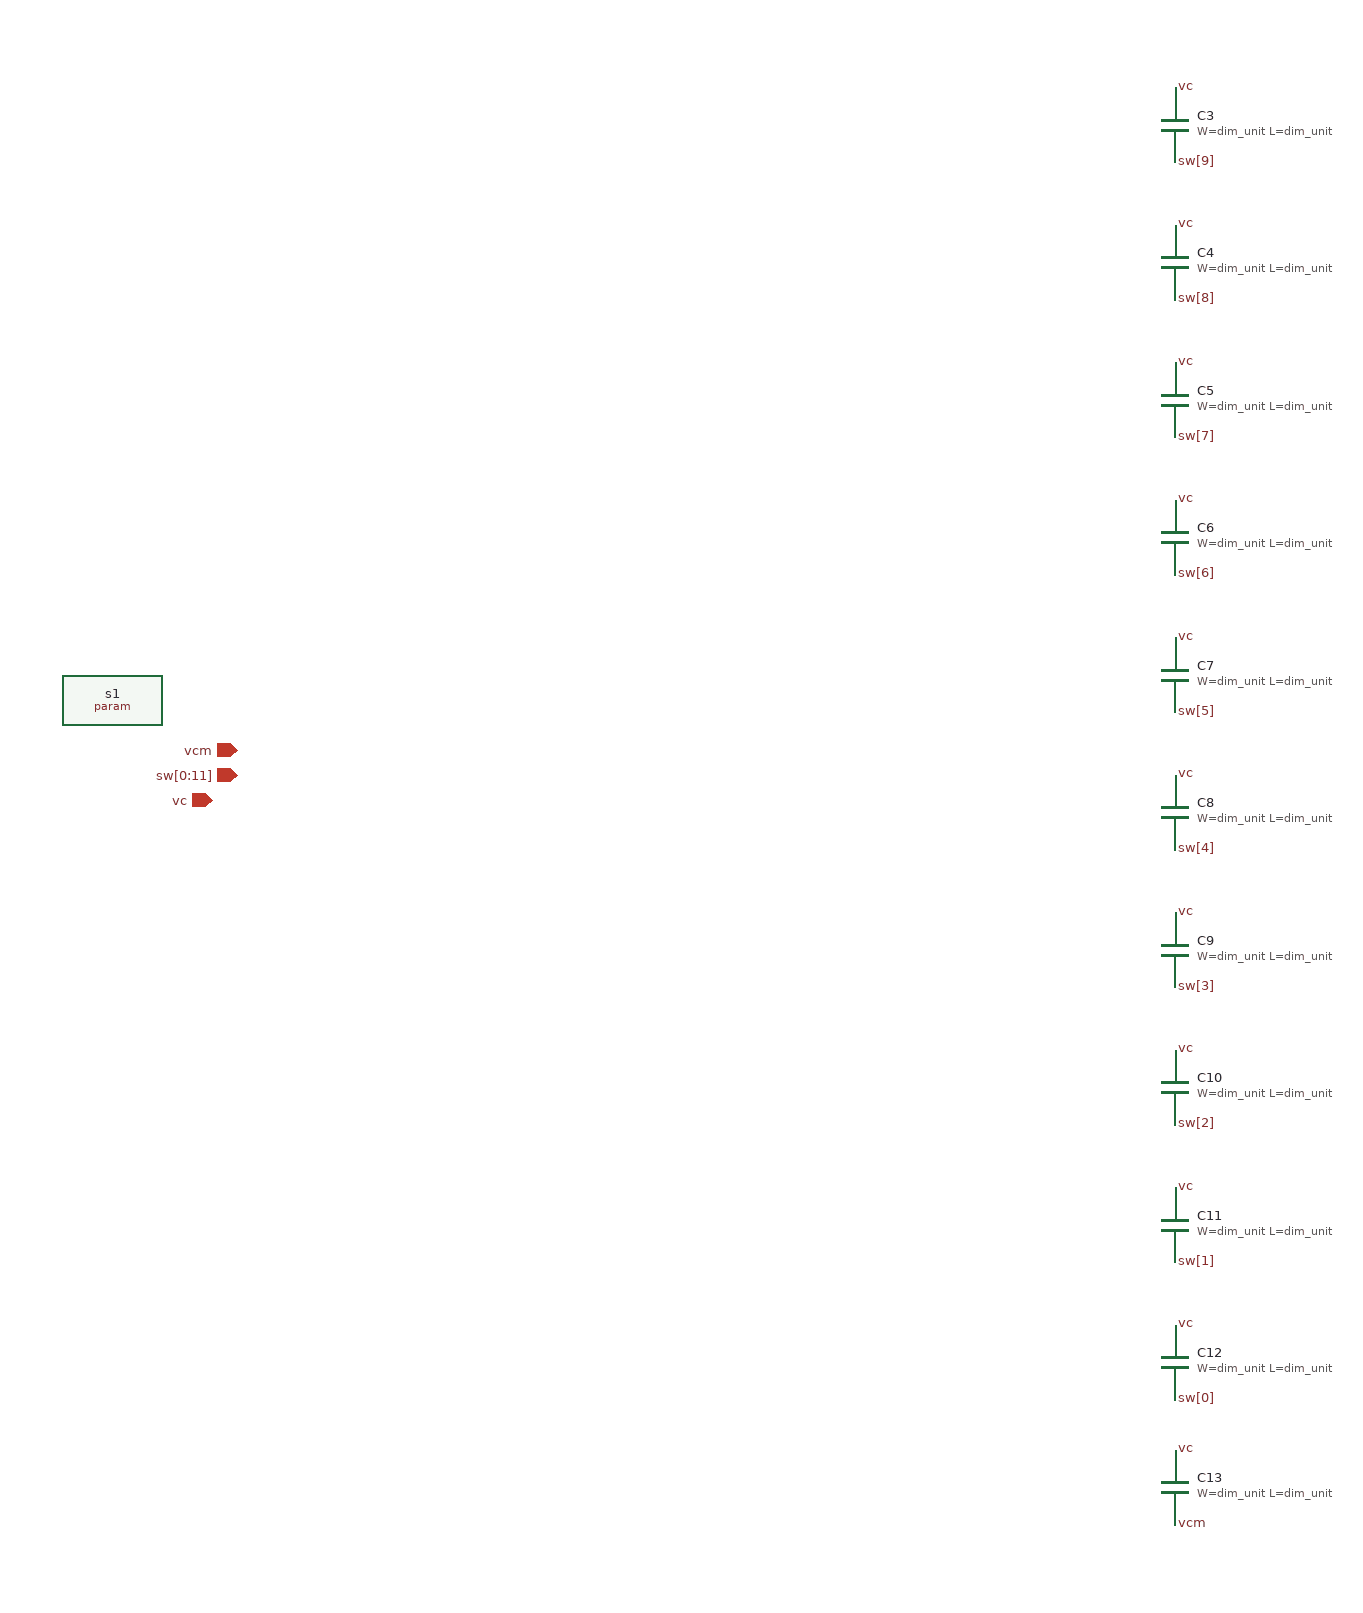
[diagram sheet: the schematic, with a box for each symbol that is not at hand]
v {xschem version=3.4.5 file_version=1.2
}
G {}
K {}
V {}
S {}
E {}
C {devices/lab_wire.sym} 960 -70 2 0 {name=p1 sig_type=std_logic lab=vcm}
C {devices/lab_wire.sym} 960 -170 2 0 {name=p3 sig_type=std_logic lab=sw[0]}
C {devices/lab_wire.sym} 960 -280 2 0 {name=p5 sig_type=std_logic lab=sw[1]}
C {devices/lab_wire.sym} 960 -390 2 0 {name=p7 sig_type=std_logic lab=sw[2]}
C {devices/lab_wire.sym} 960 -500 2 0 {name=p9 sig_type=std_logic lab=sw[3]}
C {devices/lab_wire.sym} 960 -610 2 0 {name=p11 sig_type=std_logic lab=sw[4]}
C {devices/lab_wire.sym} 960 -720 2 0 {name=p13 sig_type=std_logic lab=sw[5]}
C {devices/lab_wire.sym} 960 -830 2 0 {name=p15 sig_type=std_logic lab=sw[6]}
C {devices/lab_wire.sym} 960 -940 2 0 {name=p17 sig_type=std_logic lab=sw[7]}
C {devices/lab_wire.sym} 960 -1050 2 0 {name=p19 sig_type=std_logic lab=sw[8]}
C {devices/lab_wire.sym} 960 -1160 2 0 {name=p21 sig_type=std_logic lab=sw[9]}
C {devices/ipin.sym} 210 -670 0 0 {name=p53 lab=sw[0:11]}
C {devices/ipin.sym} 210 -690 0 0 {name=p54 lab=vcm}
C {devices/iopin.sym} 190 -650 0 0 {name=p56 lab=vc

}
C {devices/param.sym} 110 -730 0 0 {name=s1 value="dim_unit=2u"}
C {devices/lab_wire.sym} 960 -1220 0 1 {name=p30 sig_type=std_logic lab=vc}
C {sky130_fd_pr/cap_mim_m3_1.sym} 960 -1190 0 0 {name=C3 model=cap_mim_m3_1 W=dim_unit L=dim_unit MF=512 spiceprefix=X}
C {devices/lab_wire.sym} 960 -1110 0 1 {name=p31 sig_type=std_logic lab=vc}
C {sky130_fd_pr/cap_mim_m3_1.sym} 960 -1080 0 0 {name=C4 model=cap_mim_m3_1 W=dim_unit L=dim_unit MF=256 spiceprefix=X}
C {devices/lab_wire.sym} 960 -1000 0 1 {name=p32 sig_type=std_logic lab=vc}
C {sky130_fd_pr/cap_mim_m3_1.sym} 960 -970 0 0 {name=C5 model=cap_mim_m3_1 W=dim_unit L=dim_unit MF=128 spiceprefix=X}
C {devices/lab_wire.sym} 960 -890 0 1 {name=p33 sig_type=std_logic lab=vc}
C {sky130_fd_pr/cap_mim_m3_1.sym} 960 -860 0 0 {name=C6 model=cap_mim_m3_1 W=dim_unit L=dim_unit MF=64 spiceprefix=X}
C {devices/lab_wire.sym} 960 -780 0 1 {name=p34 sig_type=std_logic lab=vc}
C {sky130_fd_pr/cap_mim_m3_1.sym} 960 -750 0 0 {name=C7 model=cap_mim_m3_1 W=dim_unit L=dim_unit MF=32 spiceprefix=X}
C {devices/lab_wire.sym} 960 -670 0 1 {name=p35 sig_type=std_logic lab=vc}
C {sky130_fd_pr/cap_mim_m3_1.sym} 960 -640 0 0 {name=C8 model=cap_mim_m3_1 W=dim_unit L=dim_unit MF=16 spiceprefix=X}
C {devices/lab_wire.sym} 960 -560 0 1 {name=p36 sig_type=std_logic lab=vc}
C {sky130_fd_pr/cap_mim_m3_1.sym} 960 -530 0 0 {name=C9 model=cap_mim_m3_1 W=dim_unit L=dim_unit MF=8 spiceprefix=X}
C {devices/lab_wire.sym} 960 -450 0 1 {name=p37 sig_type=std_logic lab=vc}
C {sky130_fd_pr/cap_mim_m3_1.sym} 960 -420 0 0 {name=C10 model=cap_mim_m3_1 W=dim_unit L=dim_unit MF=4 spiceprefix=X}
C {devices/lab_wire.sym} 960 -340 0 1 {name=p38 sig_type=std_logic lab=vc}
C {sky130_fd_pr/cap_mim_m3_1.sym} 960 -310 0 0 {name=C11 model=cap_mim_m3_1 W=dim_unit L=dim_unit MF=2 spiceprefix=X}
C {devices/lab_wire.sym} 960 -230 0 1 {name=p39 sig_type=std_logic lab=vc}
C {sky130_fd_pr/cap_mim_m3_1.sym} 960 -200 0 0 {name=C12 model=cap_mim_m3_1 W=dim_unit L=dim_unit MF=1 spiceprefix=X}
C {sky130_fd_pr/cap_mim_m3_1.sym} 960 -100 0 0 {name=C13 model=cap_mim_m3_1 W=dim_unit L=dim_unit MF=1 spiceprefix=X}
C {devices/lab_wire.sym} 960 -130 0 1 {name=p71 sig_type=std_logic lab=vc}
